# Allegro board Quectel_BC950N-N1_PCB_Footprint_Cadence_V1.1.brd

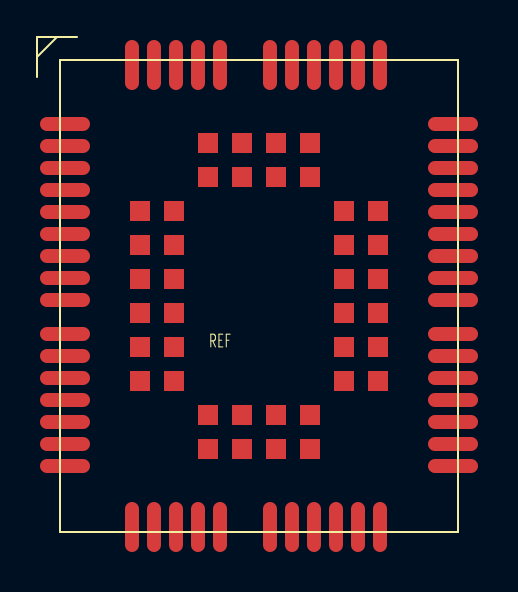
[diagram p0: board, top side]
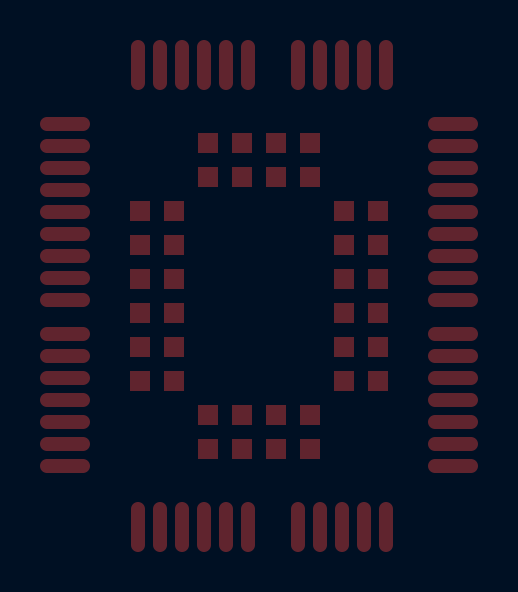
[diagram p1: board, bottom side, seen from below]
No outline. copper layers: TOP, INNER LAYER 2, INNER LAYER 3, BOTTOM. Coordinates in mm from the lowest, leftmost part position.

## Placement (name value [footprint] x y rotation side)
REF  -  [unnamed]  0 0 0 top

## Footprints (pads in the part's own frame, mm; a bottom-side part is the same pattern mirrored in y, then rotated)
unnamed
  oval 2.5x0.7 smd: 1(-9.7,8.6) 2(-9.7,7.5) 3(-9.7,6.4) 4(-9.7,5.3) 5(-9.7,4.2) 6(-9.7,3.1) 7(-9.7,2) 8(-9.7,0.9) 9(-9.7,-0.2) 10(-9.7,-1.9) 11(-9.7,-3) 12(-9.7,-4.1) 13(-9.7,-5.2) 14(-9.7,-6.3) 15(-9.7,-7.4) 16(-9.7,-8.5) 28(9.7,-8.5) 29(9.7,-7.4) 30(9.7,-6.3) 31(9.7,-5.2) 32(9.7,-4.1) 33(9.7,-3) 34(9.7,-1.9) 35(9.7,-0.2) 36(9.7,0.9) 37(9.7,2) 38(9.7,3.1) 39(9.7,4.2) 40(9.7,5.3) 41(9.7,6.4) 42(9.7,7.5) 43(9.7,8.6)
  oval 0.7x2.5 smd: 17(-6.35,-11.55) 18(-5.25,-11.55) 19(-4.15,-11.55) 20(-3.05,-11.55) 21(-1.95,-11.55) 22(0.55,-11.55) 23(1.65,-11.55) 24(2.75,-11.55) 25(3.85,-11.55) 26(4.95,-11.55) 27(6.05,-11.55) 44(6.05,11.55) 45(4.95,11.55) 46(3.85,11.55) 47(2.75,11.55) 48(1.65,11.55) 49(0.55,11.55) 50(-1.95,11.55) 51(-3.05,11.55) 52(-4.15,11.55) 53(-5.25,11.55) 54(-6.35,11.55)
  rect 1x1 smd: 55(-5.95,4.25) 56(-5.95,2.55) 57(-5.95,0.85) 58(-5.95,-0.85) 59(-5.95,-2.55) 60(-5.95,-4.25) 61(-2.55,-7.65) 62(-0.85,-7.65) 63(0.85,-7.65) 64(2.55,-7.65) 65(5.95,-4.25) 66(5.95,-2.55) 67(5.95,-0.85) 68(5.95,0.85) 69(5.95,2.55) 70(5.95,4.25) 71(2.55,7.65) 72(0.85,7.65) 73(-0.85,7.65) 74(-2.55,7.65) 75(-4.25,4.25) 76(-4.25,2.55) 77(-4.25,0.85) 78(-4.25,-0.85) 79(-4.25,-2.55) 80(-4.25,-4.25) 81(-2.55,-5.95) 82(-0.85,-5.95) 83(0.85,-5.95) 84(2.55,-5.95) 85(4.25,-4.25) 86(4.25,-2.55) 87(4.25,-0.85) 88(4.25,0.85) 89(4.25,2.55) 90(4.25,4.25) 91(2.55,5.95) 92(0.85,5.95) 93(-0.85,5.95) 94(-2.55,5.95)

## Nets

Pads without a net: REF 1 2 3 4 5 6 7 8 9 10 11 12 13 14 15 16 17 18 19 20 21 22 23 24 25 26 27 28 29 30 31 32 33 34 35 36 37 38 39 40 41 42 43 44 45 46 47 48 49 50 51 52 53 54 55 56 57 58 59 60 61 62 63 64 65 66 67 68 69 70 71 72 73 74 75 76 77 78 79 80 81 82 83 84 85 86 87 88 89 90 91 92 93 94
